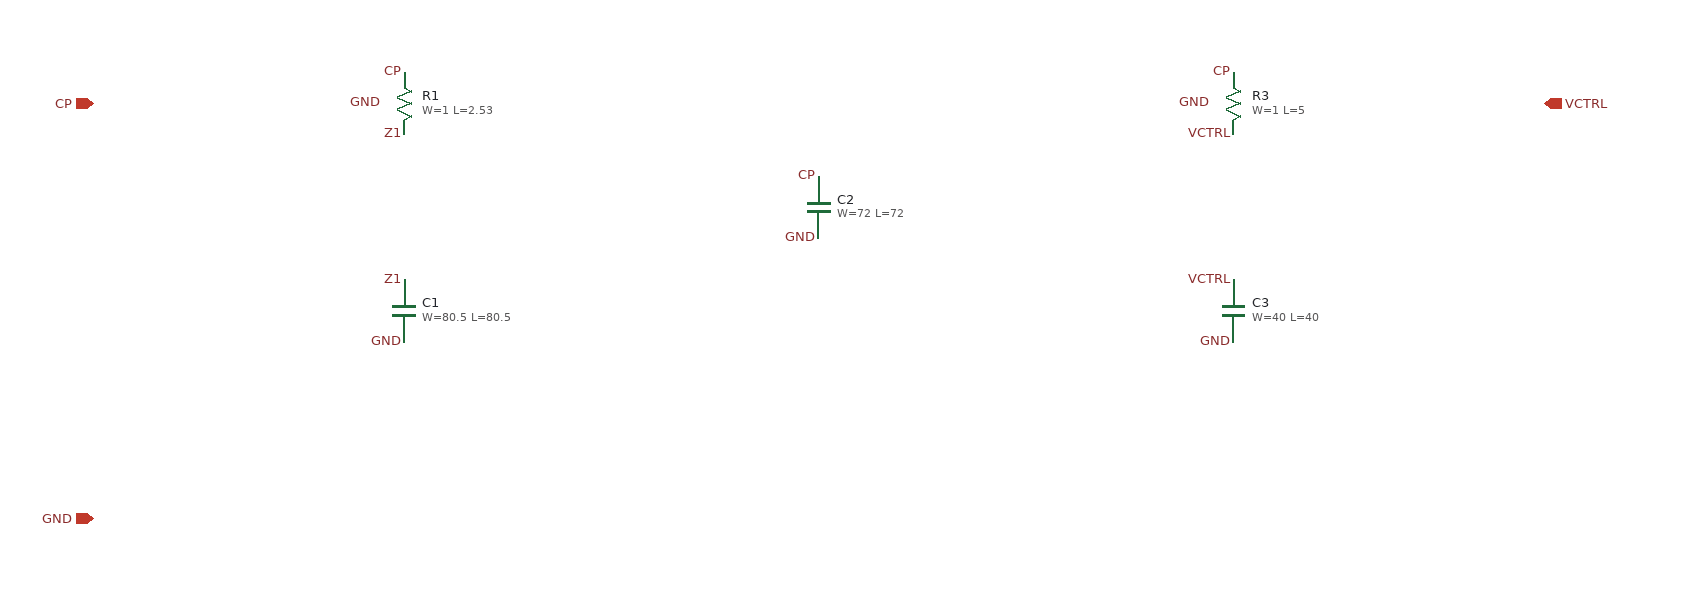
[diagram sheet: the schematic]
v {xschem version=3.4.7 file_version=1.2
* loop_filter_c1div16.sch -- a DELIBERATELY DEGRADED copy of the sky130 PLL loop filter.
* NOT part of the design: nothing under design/ instantiates it, and no spec
* row is claimed for it.
*
* Generated by sim/lf-c1-jitter-sensitivity/testbench/gen_c1_variant.py from
* design/loop-filter/loop_filter.sch. The body below is that file's own,
* verbatim, with exactly one substitution: C1's drawn geometry W=L=322 um ->
* W=L=80.5 um, i.e. C1's AREA divided by 16. R1, C2, R3 and C3 are
* untouched, and no other property of C1 changes.
*
* Why C1, and why an area divisor: C1 is the series capacitor of the R1/C1
* branch that forms the loop's compensation zero, and per
* design/loop-filter/DESIGN.md's own sizing derivation it is the single
* component that sets BOTH quantities the loop's dynamics are stated over --
* `C1 = Icp*Kv*sec(phi_m)/(2*pi*N*wc^2)` fixes the crossover, `R1*C1 =
* tan(phi_m)/wc` places the zero. Shrinking C1 therefore raises the crossover
* and drags the zero up with it, collapsing the phase margin rows 6/7 are
* stated over and leaving a badly under-damped loop whose residual phase error
* rings. That is a deliberate degradation of the loop's dynamics rather than of
* one filtering path.
*
* Why not C2 (the reference-ripple pole, the intuitive candidate):
* sim/lf-c2-jitter-sensitivity MEASURED it, and it is not a lever on this
* quantity -- see that unit's README. This arm exists because that one came
* back negative.
*
* The risk this arm carries, stated because it is the one that decides whether
* the arm is usable as a negative control at all: C1 is 94 % of the C1+C2+C3
* the cold-start acquisition ramp charges, and a loop with little phase margin
* may not reach lock inside the campaign's window. A draw that does not lock
* carries no period-jitter figure, so an arm degraded past lock is useless as a
* control however badly it behaves. Which side of that line each factor falls
* on is measured, not predicted.
*
* Verification: `--check` mode of the generator re-derives this file from the
* committed design schematic and fails on any drift, so this copy cannot fall
* out of step with the design it degrades.
}
G {}
V {}
S {}
E {}
C {sky130_fd_pr/res_xhigh_po.sym} -400 -100 0 0 {name=R1
W=1
L=2.53
mult=1
model=res_xhigh_po
spiceprefix=X}
C {devices/lab_pin.sym} -400 -70 0 0 {name=p1 sig_type=std_logic lab=Z1}
C {devices/lab_pin.sym} -400 -130 0 0 {name=p2 sig_type=std_logic lab=CP}
C {devices/lab_pin.sym} -420 -100 0 0 {name=p3 sig_type=std_logic lab=GND}
C {sky130_fd_pr/cap_mim_m3_1.sym} -400 100 0 0 {name=C1
model=cap_mim_m3_1
W=80.5
L=80.5
MF=1
spiceprefix=X}
C {devices/lab_pin.sym} -400 70 0 0 {name=p4 sig_type=std_logic lab=Z1}
C {devices/lab_pin.sym} -400 130 0 0 {name=p5 sig_type=std_logic lab=GND}
C {sky130_fd_pr/cap_mim_m3_1.sym} 0 0 0 0 {name=C2
model=cap_mim_m3_1
W=72
L=72
MF=1
spiceprefix=X}
C {devices/lab_pin.sym} 0 -30 0 0 {name=p6 sig_type=std_logic lab=CP}
C {devices/lab_pin.sym} 0 30 0 0 {name=p7 sig_type=std_logic lab=GND}
C {sky130_fd_pr/res_xhigh_po.sym} 400 -100 0 0 {name=R3
W=1
L=5
mult=1
model=res_xhigh_po
spiceprefix=X}
C {devices/lab_pin.sym} 400 -70 0 0 {name=p8 sig_type=std_logic lab=VCTRL}
C {devices/lab_pin.sym} 400 -130 0 0 {name=p9 sig_type=std_logic lab=CP}
C {devices/lab_pin.sym} 380 -100 0 0 {name=p10 sig_type=std_logic lab=GND}
C {sky130_fd_pr/cap_mim_m3_1.sym} 400 100 0 0 {name=C3
model=cap_mim_m3_1
W=40
L=40
MF=1
spiceprefix=X}
C {devices/lab_pin.sym} 400 70 0 0 {name=p11 sig_type=std_logic lab=VCTRL}
C {devices/lab_pin.sym} 400 130 0 0 {name=p12 sig_type=std_logic lab=GND}
C {devices/ipin.sym} -700 -100 0 0 {name=p13 lab=CP}
C {devices/iopin.sym} -700 300 0 0 {name=p14 lab=GND}
C {devices/opin.sym} 700 -100 0 0 {name=p15 lab=VCTRL}
C {devices/title.sym} -400 -900 0 0 {name=l1 author="2AM Logic (issue #26, sky130 PLL loop filter)"}
